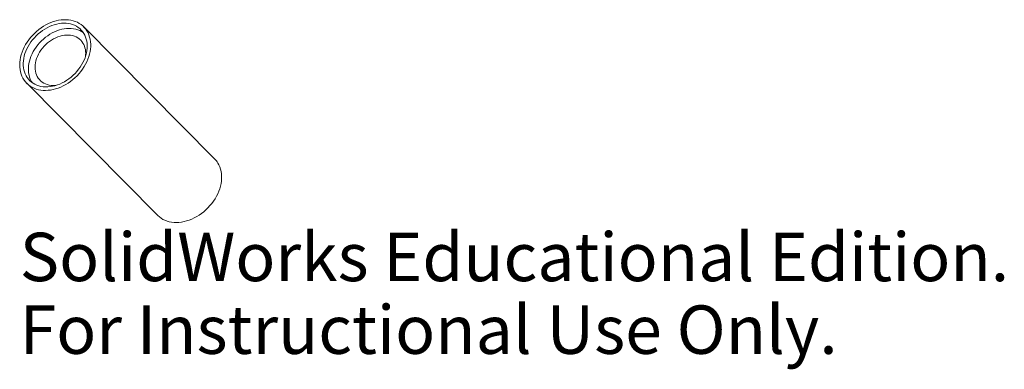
# Model space of a CAD drawing. Units: millimetres. Extents: x -16.6 to 81.5, y -18.2 to 16.7.
import ezdxf

# ---------------------------------------------------------------- set-up
doc = ezdxf.new("R2010")
doc.units = ezdxf.units.MM
doc.styles.add('SLDTEXTSTYLE0', font='TXT', dxfattribs={"width": 0.7})

msp = doc.modelspace()

# ---------------------------------------------------------------- linework, layer by layer
at = {"color": 7, "linetype": 'Continuous', "lineweight": 15}
for p, q in [((2.842, 2.815), (-10.206, 15.987)), ((-15.89, 10.357), (-2.842, -2.815))]:
    msp.add_line(p, q, dxfattribs=at)
at = {"color": 7, "linetype": 'Continuous', "lineweight": 15, "flags": 128}
for points in [[(-9.884, 15.576), (-10.006, 15.756), (-10.145, 15.923), (-10.299, 16.075), (-10.467, 16.213), (-10.648, 16.334), (-10.842, 16.439), (-11.047, 16.527), (-11.263, 16.597), (-11.488, 16.65), (-11.722, 16.685), (-11.962, 16.701), (-12.208, 16.698), (-12.458, 16.678), (-12.711, 16.639), (-12.966, 16.582), (-13.222, 16.507), (-13.476, 16.415), (-13.729, 16.306), (-13.978, 16.181), (-14.222, 16.04), (-14.46, 15.884), (-14.69, 15.714), (-14.912, 15.53), (-15.124, 15.335), (-15.326, 15.128), (-15.515, 14.91), (-15.692, 14.684), (-15.855, 14.45), (-16.003, 14.209), (-16.136, 13.963), (-16.253, 13.713), (-16.353, 13.46), (-16.436, 13.205), (-16.501, 12.95), (-16.548, 12.697), (-16.577, 12.446), (-16.587, 12.198), (-16.579, 11.956), (-16.553, 11.72), (-16.508, 11.492), (-16.446, 11.272), (-16.365, 11.063), (-16.268, 10.864), (-16.153, 10.677), (-16.023, 10.504), (-15.877, 10.344), (-15.716, 10.199), (-15.541, 10.069), (-15.353, 9.956), (-15.153, 9.859), (-14.942, 9.78), (-14.722, 9.719), (-14.492, 9.675), (-14.256, 9.65), (-14.012, 9.643), (-13.764, 9.654), (-13.512, 9.684), (-13.258, 9.732), (-13.002, 9.798), (-12.747, 9.881), (-12.493, 9.982), (-12.243, 10.099), (-11.996, 10.232), (-11.755, 10.381), (-11.521, 10.544), (-11.294, 10.721), (-11.077, 10.911), (-10.87, 11.112), (-10.674, 11.324), (-10.491, 11.546), (-10.321, 11.776), (-10.166, 12.014), (-10.025, 12.258), (-9.9, 12.506), (-9.792, 12.758), (-9.7, 13.012), (-9.626, 13.267), (-9.57, 13.521), (-9.532, 13.774), (-9.512, 14.023), (-9.511, 14.268), (-9.528, 14.507), (-9.563, 14.74), (-9.617, 14.964), (-9.689, 15.179), (-9.778, 15.383), (-9.884, 15.576)], [(-10.2, 15.335), (-10.316, 15.505), (-10.448, 15.661), (-10.595, 15.804), (-10.755, 15.931), (-10.929, 16.042), (-11.115, 16.137), (-11.312, 16.215), (-11.519, 16.275), (-11.735, 16.318), (-11.958, 16.342), (-12.187, 16.349), (-12.422, 16.337), (-12.66, 16.307), (-12.9, 16.259), (-13.141, 16.194), (-13.381, 16.111), (-13.62, 16.012), (-13.855, 15.896), (-14.086, 15.764), (-14.311, 15.618), (-14.528, 15.458), (-14.737, 15.284), (-14.937, 15.099), (-15.125, 14.902), (-15.302, 14.696), (-15.466, 14.48), (-15.616, 14.258), (-15.751, 14.029), (-15.871, 13.795), (-15.974, 13.558), (-16.061, 13.318), (-16.131, 13.078), (-16.182, 12.838), (-16.216, 12.6), (-16.232, 12.365), (-16.23, 12.135), (-16.209, 11.911), (-16.17, 11.694), (-16.114, 11.486), (-16.039, 11.287), (-15.948, 11.099), (-15.84, 10.923), (-15.716, 10.76), (-15.577, 10.61), (-15.423, 10.475), (-15.256, 10.356), (-15.076, 10.253), (-14.884, 10.167), (-14.682, 10.098), (-14.471, 10.046), (-14.251, 10.012), (-14.025, 9.997), (-13.793, 9.999), (-13.556, 10.02), (-13.317, 10.059), (-13.076, 10.116), (-12.835, 10.19), (-12.595, 10.281), (-12.358, 10.389), (-12.125, 10.513), (-11.897, 10.652), (-11.676, 10.805), (-11.462, 10.972), (-11.258, 11.152), (-11.064, 11.343), (-10.881, 11.545), (-10.711, 11.756), (-10.554, 11.975), (-10.411, 12.201), (-10.284, 12.432), (-10.172, 12.668), (-10.077, 12.907), (-9.998, 13.147), (-9.938, 13.387), (-9.895, 13.626), (-9.87, 13.863), (-9.863, 14.095), (-9.875, 14.322), (-9.904, 14.543), (-9.952, 14.756), (-10.018, 14.96), (-10.101, 15.153), (-10.2, 15.335)], [(-10.258, 15.424), (-10.416, 15.524), (-10.602, 15.619), (-10.799, 15.697), (-11.006, 15.758), (-11.222, 15.8), (-11.445, 15.825), (-11.675, 15.831), (-11.909, 15.82), (-12.147, 15.79), (-12.387, 15.742), (-12.628, 15.677), (-12.869, 15.594), (-13.107, 15.494), (-13.343, 15.378), (-13.573, 15.247), (-13.798, 15.1), (-14.016, 14.94), (-14.225, 14.767), (-14.424, 14.581), (-14.613, 14.385), (-14.789, 14.178), (-14.953, 13.963), (-15.103, 13.74), (-15.238, 13.511), (-15.358, 13.277), (-15.462, 13.04), (-15.548, 12.801), (-15.618, 12.56), (-15.67, 12.32), (-15.704, 12.082), (-15.72, 11.848), (-15.717, 11.618), (-15.696, 11.393), (-15.658, 11.177), (-15.601, 10.968), (-15.527, 10.769), (-15.435, 10.581), (-15.327, 10.405), (-15.326, 10.403)], [(-10.281, 14.367), (-10.386, 14.519), (-10.508, 14.657), (-10.644, 14.781), (-10.794, 14.888), (-10.958, 14.979), (-11.133, 15.053), (-11.318, 15.109), (-11.512, 15.147), (-11.714, 15.167), (-11.922, 15.168), (-12.135, 15.15), (-12.35, 15.114), (-12.567, 15.06), (-12.784, 14.987), (-12.999, 14.898), (-13.21, 14.792), (-13.416, 14.67), (-13.616, 14.533), (-13.808, 14.382), (-13.99, 14.219), (-14.162, 14.044), (-14.322, 13.858), (-14.468, 13.664), (-14.6, 13.462), (-14.717, 13.255), (-14.818, 13.042), (-14.901, 12.827), (-14.968, 12.611), (-15.016, 12.395), (-15.046, 12.181), (-15.057, 11.97), (-15.05, 11.765), (-15.024, 11.566), (-14.979, 11.375), (-14.917, 11.194), (-14.837, 11.023), (-14.74, 10.865), (-14.626, 10.72), (-14.497, 10.589), (-14.354, 10.473), (-14.197, 10.374), (-14.027, 10.291), (-13.847, 10.226), (-13.657, 10.179), (-13.459, 10.15), (-13.254, 10.14), (-13.043, 10.148), (-12.921, 10.162)], [(-2.842, -2.815), (-2.828, -2.829), (-2.667, -2.973), (-2.493, -3.103), (-2.305, -3.216), (-2.105, -3.313), (-1.894, -3.392), (-1.674, -3.454), (-1.444, -3.497), (-1.207, -3.523), (-0.964, -3.53), (-0.716, -3.518), (-0.464, -3.488), (-0.21, -3.44), (0.046, -3.375), (0.301, -3.291), (0.555, -3.19), (0.806, -3.073), (1.052, -2.94), (1.293, -2.791), (1.528, -2.628), (1.754, -2.451), (1.971, -2.262), (2.178, -2.06), (2.374, -1.848), (2.557, -1.626), (2.727, -1.396), (2.883, -1.158), (3.023, -0.915), (3.148, -0.666), (3.257, -0.414), (3.348, -0.16), (3.422, 0.094), (3.478, 0.349), (3.516, 0.601), (3.536, 0.851), (3.537, 1.096), (3.52, 1.335), (3.485, 1.567), (3.431, 1.791), (3.36, 2.006), (3.27, 2.211), (3.164, 2.403)]]:
    msp.add_lwpolyline(points, dxfattribs=at)
at = {"color": 7, "linetype": 'Continuous', "lineweight": 15}
for centre, radius, start, end in [((-12.058, 13.351), 2.047, 350.57441, 29.75076), ((1.231, 1.22), 2.267, 31.45846, 44.70693)]:
    msp.add_arc(centre, radius, start, end, dxfattribs=at)

# ---------------------------------------------------------------- texts
at = {"color": 7, "linetype": 'Continuous', "char_height": 4.83362, "attachment_point": 1, "style": 'SLDTEXTSTYLE0'}
for s, insert in [('SolidWorks Educational Edition.', (-16.587, -4.549)), ('For Instructional Use Only.', (-16.587, -11.8))]:
    msp.add_mtext(s, dxfattribs=dict(at, insert=insert))

doc.saveas('drawing.dxf')
